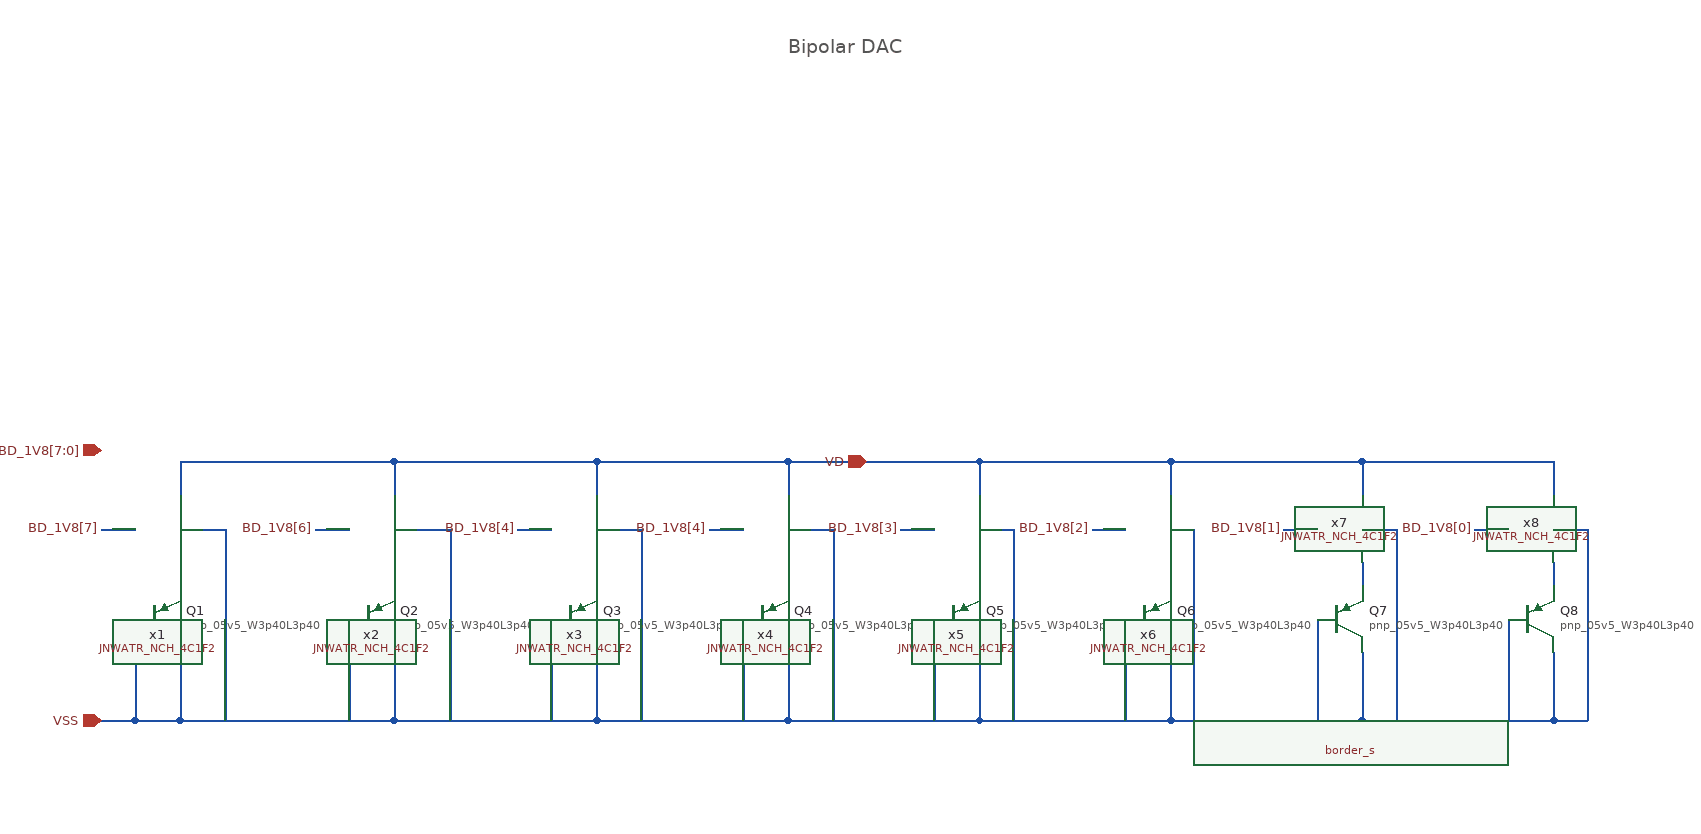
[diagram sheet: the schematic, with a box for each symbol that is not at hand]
v {xschem version=3.4.5 file_version=1.2
}
G {}
K {}
V {}
S {}
E {}
T {Bipolar DAC} 770 -810 0 0 0.5 0.5 {}
N 230 -260 230 -200 {
lab=VSS}
N 190 -290 190 -200 {
lab=VSS}
N 190 -200 230 -200 {
lab=VSS}
N 230 -200 420 -200 {
lab=VSS}
N 420 -260 420 -200 {
lab=VSS}
N 420 -200 600 -200 {
lab=VSS}
N 600 -260 600 -200 {
lab=VSS}
N 600 -200 770 -200 {
lab=VSS}
N 770 -260 770 -200 {
lab=VSS}
N 730 -290 730 -200 {
lab=VSS}
N 560 -290 560 -200 {
lab=VSS}
N 380 -290 380 -200 {
lab=VSS}
N 770 -200 940 -200 {
lab=VSS}
N 940 -260 940 -200 {
lab=VSS}
N 900 -290 900 -200 {
lab=VSS}
N 940 -200 1110 -200 {
lab=VSS}
N 1110 -260 1110 -200 {
lab=VSS}
N 1070 -290 1070 -200 {
lab=VSS}
N 1110 -200 1280 -200 {
lab=VSS}
N 1280 -260 1280 -200 {
lab=VSS}
N 1240 -290 1240 -200 {
lab=VSS}
N 1280 -200 1450 -200 {
lab=VSS}
N 1450 -260 1450 -200 {
lab=VSS}
N 1410 -290 1410 -200 {
lab=VSS}
N 1450 -340 1450 -320 {
lab=#net1}
N 1280 -340 1280 -320 {
lab=#net2}
N 1110 -340 1110 -320 {
lab=#net3}
N 940 -340 940 -320 {
lab=#net4}
N 770 -340 770 -320 {
lab=#net5}
N 600 -340 600 -320 {
lab=#net6}
N 420 -340 420 -320 {
lab=#net7}
N 230 -340 230 -320 {
lab=#net8}
N 230 -370 270 -370 {
lab=VSS}
N 270 -370 270 -200 {
lab=VSS}
N 420 -370 470 -370 {
lab=VSS}
N 470 -370 470 -200 {
lab=VSS}
N 600 -370 640 -370 {
lab=VSS}
N 640 -370 640 -200 {
lab=VSS}
N 770 -370 810 -370 {
lab=VSS}
N 810 -370 810 -200 {
lab=VSS}
N 940 -370 970 -370 {
lab=VSS}
N 970 -370 970 -200 {
lab=VSS}
N 1110 -370 1130 -370 {
lab=VSS}
N 1130 -370 1130 -200 {
lab=VSS}
N 1280 -370 1310 -370 {
lab=VSS}
N 1310 -370 1310 -200 {
lab=VSS}
N 1450 -370 1480 -370 {
lab=VSS}
N 1480 -370 1480 -200 {
lab=VSS}
N 1450 -200 1480 -200 {
lab=VSS}
N 230 -430 230 -400 {
lab=VD}
N 230 -430 420 -430 {
lab=VD}
N 420 -430 420 -400 {
lab=VD}
N 420 -430 600 -430 {
lab=VD}
N 600 -430 600 -410 {
lab=VD}
N 600 -410 600 -400 {
lab=VD}
N 770 -430 770 -400 {
lab=VD}
N 600 -430 770 -430 {
lab=VD}
N 940 -430 940 -400 {
lab=VD}
N 770 -430 940 -430 {
lab=VD}
N 1110 -430 1110 -400 {
lab=VD}
N 940 -430 1110 -430 {
lab=VD}
N 1280 -430 1280 -400 {
lab=VD}
N 1110 -430 1280 -430 {
lab=VD}
N 1450 -430 1450 -400 {
lab=VD}
N 1280 -430 1450 -430 {
lab=VD}
N 160 -200 190 -200 {
lab=VSS}
N 160 -370 190 -370 {
lab=BD_1V8[7]}
N 350 -370 380 -370 {
lab=BD_1V8[6]}
N 530 -370 560 -370 {
lab=BD_1V8[4]}
N 700 -370 730 -370 {
lab=BD_1V8[4]}
N 870 -370 900 -370 {
lab=BD_1V8[3]}
N 1040 -370 1070 -370 {
lab=BD_1V8[2]}
N 1210 -370 1240 -370 {
lab=BD_1V8[1]}
N 1380 -370 1410 -370 {
lab=BD_1V8[0]}
C {sky130_fd_pr/pnp_05v5.sym} 210 -290 0 0 {name=Q1
model=pnp_05v5_W3p40L3p40
spiceprefix=X
}
C {sky130_fd_pr/pnp_05v5.sym} 400 -290 0 0 {name=Q2
model=pnp_05v5_W3p40L3p40
spiceprefix=X
}
C {sky130_fd_pr/pnp_05v5.sym} 580 -290 0 0 {name=Q3
model=pnp_05v5_W3p40L3p40
spiceprefix=X
}
C {sky130_fd_pr/pnp_05v5.sym} 750 -290 0 0 {name=Q4
model=pnp_05v5_W3p40L3p40
spiceprefix=X
}
C {sky130_fd_pr/pnp_05v5.sym} 920 -290 0 0 {name=Q5
model=pnp_05v5_W3p40L3p40
spiceprefix=X
}
C {sky130_fd_pr/pnp_05v5.sym} 1090 -290 0 0 {name=Q6
model=pnp_05v5_W3p40L3p40
spiceprefix=X
}
C {sky130_fd_pr/pnp_05v5.sym} 1260 -290 0 0 {name=Q7
model=pnp_05v5_W3p40L3p40
spiceprefix=X
}
C {sky130_fd_pr/pnp_05v5.sym} 1430 -290 0 0 {name=Q8
model=pnp_05v5_W3p40L3p40
spiceprefix=X
}
C {JNW_ATR_SKY130NM/JNWATR_NCH_4C1F2.sym} 190 -370 0 0 {name=x1 }
C {JNW_ATR_SKY130NM/JNWATR_NCH_4C1F2.sym} 380 -370 0 0 {name=x2 }
C {JNW_ATR_SKY130NM/JNWATR_NCH_4C1F2.sym} 560 -370 0 0 {name=x3 }
C {JNW_ATR_SKY130NM/JNWATR_NCH_4C1F2.sym} 730 -370 0 0 {name=x4 }
C {JNW_ATR_SKY130NM/JNWATR_NCH_4C1F2.sym} 900 -370 0 0 {name=x5 }
C {JNW_ATR_SKY130NM/JNWATR_NCH_4C1F2.sym} 1070 -370 0 0 {name=x6 }
C {JNW_ATR_SKY130NM/JNWATR_NCH_4C1F2.sym} 1240 -370 0 0 {name=x7 }
C {JNW_ATR_SKY130NM/JNWATR_NCH_4C1F2.sym} 1410 -370 0 0 {name=x8 }
C {devices/ipin.sym} 160 -200 0 0 {name=p1 lab=VSS}
C {devices/iopin.sym} 840 -430 3 0 {name=p2 lab=VD}
C {devices/ipin.sym} 160 -440 0 0 {name=p3 lab=BD_1V8[7:0]}
C {devices/lab_wire.sym} 160 -370 0 0 {name=p4 sig_type=std_logic lab=BD_1V8[7]}
C {devices/lab_wire.sym} 350 -370 0 0 {name=p5 sig_type=std_logic lab=BD_1V8[6]}
C {devices/lab_wire.sym} 530 -370 0 0 {name=p6 sig_type=std_logic lab=BD_1V8[4]}
C {devices/lab_wire.sym} 700 -370 0 0 {name=p7 sig_type=std_logic lab=BD_1V8[4]}
C {devices/lab_wire.sym} 870 -370 0 0 {name=p8 sig_type=std_logic lab=BD_1V8[3]}
C {devices/lab_wire.sym} 1040 -370 0 0 {name=p9 sig_type=std_logic lab=BD_1V8[2]}
C {devices/lab_wire.sym} 1210 -370 0 0 {name=p10 sig_type=std_logic lab=BD_1V8[1]}
C {devices/lab_wire.sym} 1380 -370 0 0 {name=p11 sig_type=std_logic lab=BD_1V8[0]}
C {cborder/border_s.sym} 1250 -170 0 0 {
user="Carsten Wulff"
company="Carsten Wulff Software"}
